VERSION 5.7 ;
  NOWIREEXTENSIONATPIN ON ;
  DIVIDERCHAR "/" ;
  BUSBITCHARS "[]" ;
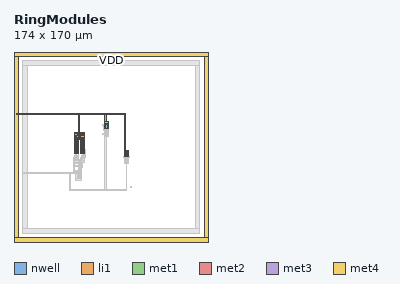
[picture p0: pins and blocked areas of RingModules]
MACRO RingModules
  CLASS BLOCK ;
  FOREIGN RingModules ;
  ORIGIN 12.000 8.000 ;
  SIZE 174.000 BY 170.000 ;
  PIN VDD
    ANTENNADIFFAREA 31.667999 ;
    PORT
      LAYER nwell ;
        RECT 69.250 93.250 72.330 98.220 ;
        RECT 42.340 80.320 45.420 86.020 ;
        RECT 42.330 71.550 45.420 80.320 ;
        RECT 42.330 71.320 45.410 71.550 ;
        RECT 47.890 71.490 50.970 85.960 ;
        RECT 87.170 68.400 90.250 72.370 ;
      LAYER li1 ;
        RECT 69.210 97.520 72.410 99.380 ;
        RECT 69.210 93.810 69.850 97.520 ;
        RECT 71.640 93.810 72.410 97.520 ;
        RECT 69.210 93.640 72.410 93.810 ;
        RECT 69.210 93.550 69.850 93.640 ;
        RECT 71.640 93.580 72.410 93.640 ;
        RECT 69.330 93.530 69.850 93.550 ;
        RECT 69.520 93.520 69.850 93.530 ;
        RECT 42.340 85.550 45.450 90.160 ;
        RECT 42.730 85.460 45.030 85.550 ;
        RECT 47.890 85.480 51.000 90.090 ;
        RECT 42.730 72.110 42.900 85.460 ;
        RECT 43.400 73.015 43.570 84.555 ;
        RECT 44.860 72.110 45.030 85.460 ;
        RECT 42.730 71.940 45.030 72.110 ;
        RECT 48.280 85.400 50.580 85.480 ;
        RECT 48.280 72.050 48.450 85.400 ;
        RECT 48.950 72.955 49.120 84.495 ;
        RECT 50.410 72.050 50.580 85.400 ;
        RECT 48.280 71.880 50.580 72.050 ;
        RECT 86.740 71.800 90.610 73.990 ;
        RECT 86.740 68.960 87.740 71.800 ;
        RECT 87.990 70.905 88.290 71.800 ;
        RECT 87.990 70.400 88.400 70.905 ;
        RECT 88.230 69.865 88.400 70.400 ;
        RECT 89.680 68.960 90.610 71.800 ;
        RECT 86.740 68.800 90.610 68.960 ;
        RECT 87.560 68.790 89.860 68.800 ;
      LAYER met1 ;
        RECT 34.520 107.090 35.520 107.120 ;
        RECT 34.520 106.090 87.870 107.090 ;
        RECT 34.520 106.060 35.520 106.090 ;
        RECT 46.050 89.840 47.050 106.090 ;
        RECT 69.340 99.390 70.340 106.090 ;
        RECT 69.200 98.100 72.360 99.390 ;
        RECT 43.220 89.810 50.550 89.840 ;
        RECT 42.460 89.800 50.550 89.810 ;
        RECT 42.460 88.840 50.810 89.800 ;
        RECT 42.460 87.710 45.220 88.840 ;
        RECT 48.050 88.140 50.810 88.840 ;
        RECT 46.740 87.715 50.810 88.140 ;
        RECT 43.170 84.535 43.480 87.710 ;
        RECT 46.740 85.770 47.165 87.715 ;
        RECT 48.050 87.700 50.810 87.715 ;
        RECT 43.170 83.870 43.600 84.535 ;
        RECT 43.370 73.035 43.600 83.870 ;
        RECT 46.730 84.180 47.170 84.210 ;
        RECT 48.920 84.180 49.150 84.475 ;
        RECT 46.730 83.740 49.150 84.180 ;
        RECT 46.730 83.710 47.170 83.740 ;
        RECT 48.920 72.975 49.150 83.740 ;
        RECT 86.870 73.990 87.870 106.090 ;
        RECT 86.740 73.390 90.610 73.990 ;
        RECT 86.740 71.920 90.650 73.390 ;
        RECT 86.740 71.800 90.610 71.920 ;
        RECT 87.990 70.885 88.290 71.800 ;
        RECT 87.990 70.400 88.430 70.885 ;
        RECT 88.200 69.885 88.430 70.400 ;
      LAYER met2 ;
        RECT 11.560 106.090 35.550 107.090 ;
        RECT 11.560 106.045 12.560 106.090 ;
        RECT 46.740 86.225 47.165 86.250 ;
        RECT 46.710 85.800 47.195 86.225 ;
        RECT 46.740 84.180 47.165 85.800 ;
        RECT 46.700 83.740 47.200 84.180 ;
      LAYER met3 ;
        RECT -10.090 106.065 12.585 107.065 ;
      LAYER met4 ;
        RECT -12.000 158.000 162.000 162.000 ;
        RECT -12.000 -4.000 -8.000 158.000 ;
        RECT 158.000 -4.000 162.000 158.000 ;
        RECT -12.000 -8.000 162.000 -4.000 ;
    END
  END VDD
  OBS
      LAYER pwell ;
        RECT 69.340 87.780 72.140 91.360 ;
        RECT 42.460 65.910 45.260 69.640 ;
        RECT 48.060 65.960 50.860 69.690 ;
        RECT 87.320 64.120 90.100 67.700 ;
        RECT 45.340 49.210 48.140 61.240 ;
      LAYER li1 ;
        RECT 70.540 96.970 71.040 97.140 ;
        RECT 70.310 94.715 70.480 96.755 ;
        RECT 71.100 94.715 71.270 96.755 ;
        RECT 70.540 94.330 71.040 94.500 ;
        RECT 69.260 91.120 69.790 91.220 ;
        RECT 71.670 91.120 72.200 91.180 ;
        RECT 69.260 90.950 72.200 91.120 ;
        RECT 69.260 88.190 69.790 90.950 ;
        RECT 70.490 90.260 70.990 90.430 ;
        RECT 70.260 89.050 70.430 90.090 ;
        RECT 71.050 89.050 71.220 90.090 ;
        RECT 70.490 88.710 70.990 88.880 ;
        RECT 71.670 88.190 72.200 90.950 ;
        RECT 69.260 87.030 72.200 88.190 ;
        RECT 69.270 86.300 72.200 87.030 ;
        RECT 43.630 84.770 44.130 84.940 ;
        RECT 49.180 84.710 49.680 84.880 ;
        RECT 44.190 73.015 44.360 84.555 ;
        RECT 49.740 72.955 49.910 84.495 ;
        RECT 43.630 72.630 44.130 72.800 ;
        RECT 49.180 72.570 49.680 72.740 ;
        RECT 88.460 71.120 88.960 71.290 ;
        RECT 89.020 69.865 89.190 70.905 ;
        RECT 88.460 69.480 88.960 69.650 ;
        RECT 42.700 69.230 45.020 69.400 ;
        RECT 42.700 66.360 42.870 69.230 ;
        RECT 43.610 68.540 44.110 68.710 ;
        RECT 43.380 67.180 43.550 68.370 ;
        RECT 44.170 67.180 44.340 68.370 ;
        RECT 43.610 66.840 44.110 67.010 ;
        RECT 44.850 66.360 45.020 69.230 ;
        RECT 48.300 69.280 50.620 69.450 ;
        RECT 48.300 66.440 48.470 69.280 ;
        RECT 49.210 68.590 49.710 68.760 ;
        RECT 48.980 67.230 49.150 68.420 ;
        RECT 49.770 67.230 49.940 68.420 ;
        RECT 49.210 66.890 49.710 67.060 ;
        RECT 48.030 66.370 49.910 66.440 ;
        RECT 50.450 66.370 50.620 69.280 ;
        RECT 86.720 67.290 90.610 67.460 ;
        RECT 42.440 65.050 45.290 66.360 ;
        RECT 42.430 63.060 45.300 65.050 ;
        RECT 48.030 63.565 50.940 66.370 ;
        RECT 86.720 64.540 87.730 67.290 ;
        RECT 88.460 66.600 88.960 66.770 ;
        RECT 88.230 65.790 88.400 66.430 ;
        RECT 87.990 65.390 88.400 65.790 ;
        RECT 89.020 65.390 89.190 66.430 ;
        RECT 87.990 64.540 88.290 65.390 ;
        RECT 88.460 65.050 88.960 65.220 ;
        RECT 89.670 64.540 90.610 67.290 ;
        RECT 86.720 63.820 90.610 64.540 ;
        RECT 48.060 63.010 50.940 63.565 ;
        RECT 86.710 62.350 90.620 63.820 ;
        RECT 45.580 60.830 47.900 61.000 ;
        RECT 45.580 49.620 45.750 60.830 ;
        RECT 46.490 60.140 46.990 60.310 ;
        RECT 46.260 50.480 46.430 59.970 ;
        RECT 47.050 50.480 47.220 59.970 ;
        RECT 46.490 50.140 46.990 50.310 ;
        RECT 47.730 49.620 47.900 60.830 ;
        RECT 45.580 49.580 47.900 49.620 ;
        RECT 45.330 46.760 48.170 49.580 ;
      LAYER met1 ;
        RECT 67.060 97.225 68.060 97.550 ;
        RECT 67.060 97.170 70.885 97.225 ;
        RECT 67.060 96.940 71.020 97.170 ;
        RECT 67.060 96.875 70.900 96.940 ;
        RECT 67.060 96.550 68.060 96.875 ;
        RECT 70.280 95.785 70.510 96.735 ;
        RECT 67.945 95.430 70.510 95.785 ;
        RECT 67.945 92.370 68.300 95.430 ;
        RECT 70.280 94.735 70.510 95.430 ;
        RECT 70.670 94.530 70.900 96.875 ;
        RECT 71.070 95.775 71.300 96.735 ;
        RECT 71.070 95.525 72.575 95.775 ;
        RECT 71.070 94.735 71.300 95.525 ;
        RECT 70.560 94.300 71.020 94.530 ;
        RECT 70.670 94.270 70.900 94.300 ;
        RECT 68.630 92.370 69.630 92.690 ;
        RECT 72.325 92.680 72.575 95.525 ;
        RECT 67.945 92.340 69.630 92.370 ;
        RECT 67.945 92.040 71.410 92.340 ;
        RECT 67.945 92.015 69.630 92.040 ;
        RECT 68.630 91.690 69.630 92.015 ;
        RECT 68.980 90.810 69.240 91.130 ;
        RECT 69.010 89.555 69.210 90.810 ;
        RECT 70.510 90.230 70.970 90.460 ;
        RECT 70.230 89.610 70.460 90.070 ;
        RECT 70.130 89.555 70.460 89.610 ;
        RECT 69.010 89.355 70.460 89.555 ;
        RECT 67.280 88.875 68.280 89.350 ;
        RECT 70.130 89.300 70.460 89.355 ;
        RECT 70.230 89.070 70.460 89.300 ;
        RECT 70.680 88.910 70.820 90.230 ;
        RECT 71.110 90.070 71.410 92.040 ;
        RECT 71.950 91.680 72.950 92.680 ;
        RECT 72.355 91.255 72.550 91.680 ;
        RECT 72.325 90.935 72.585 91.255 ;
        RECT 71.020 89.430 71.410 90.070 ;
        RECT 71.020 89.070 71.250 89.430 ;
        RECT 70.510 88.875 70.970 88.910 ;
        RECT 67.280 88.645 70.975 88.875 ;
        RECT 67.280 88.350 68.280 88.645 ;
        RECT 69.430 87.410 70.430 87.470 ;
        RECT 69.230 86.290 72.200 87.410 ;
        RECT 43.650 84.910 44.110 84.970 ;
        RECT 43.650 84.740 49.660 84.910 ;
        RECT 43.770 72.855 43.970 84.740 ;
        RECT 49.200 84.680 49.660 84.740 ;
        RECT 44.160 74.320 44.390 84.535 ;
        RECT 44.160 73.970 45.880 74.320 ;
        RECT 44.160 73.035 44.390 73.970 ;
        RECT 45.530 72.855 45.880 73.970 ;
        RECT 43.725 72.830 45.880 72.855 ;
        RECT 43.650 72.600 45.880 72.830 ;
        RECT 49.340 72.770 49.570 84.680 ;
        RECT 49.710 74.330 49.940 84.475 ;
        RECT 49.710 74.320 51.750 74.330 ;
        RECT 49.710 73.970 51.770 74.320 ;
        RECT 49.710 72.975 49.940 73.970 ;
        RECT 43.725 72.505 45.880 72.600 ;
        RECT 49.200 72.540 49.660 72.770 ;
        RECT 43.350 70.120 44.350 71.120 ;
        RECT 43.780 68.740 43.940 70.120 ;
        RECT 43.630 68.510 44.090 68.740 ;
        RECT 43.350 68.020 43.580 68.350 ;
        RECT 41.480 67.640 43.580 68.020 ;
        RECT 41.480 62.270 41.860 67.640 ;
        RECT 43.350 67.200 43.580 67.640 ;
        RECT 43.780 67.040 43.940 68.510 ;
        RECT 44.140 68.020 44.370 68.350 ;
        RECT 45.530 68.020 45.880 72.505 ;
        RECT 48.980 70.190 49.980 71.190 ;
        RECT 51.370 71.120 51.770 73.970 ;
        RECT 49.370 68.790 49.575 70.190 ;
        RECT 51.130 70.120 52.130 71.120 ;
        RECT 49.230 68.560 49.690 68.790 ;
        RECT 51.370 68.770 51.770 70.120 ;
        RECT 48.950 68.020 49.180 68.400 ;
        RECT 44.140 67.675 45.880 68.020 ;
        RECT 44.140 67.670 45.840 67.675 ;
        RECT 44.140 67.200 44.370 67.670 ;
        RECT 47.440 67.590 49.180 68.020 ;
        RECT 43.630 66.810 44.090 67.040 ;
        RECT 45.940 65.780 46.480 65.810 ;
        RECT 42.860 65.240 46.480 65.780 ;
        RECT 42.860 64.760 43.450 65.240 ;
        RECT 45.940 65.210 46.480 65.240 ;
        RECT 42.410 63.320 45.270 64.760 ;
        RECT 47.455 62.305 47.860 67.590 ;
        RECT 48.950 67.250 49.180 67.590 ;
        RECT 49.370 67.090 49.575 68.560 ;
        RECT 49.740 68.010 49.970 68.400 ;
        RECT 51.370 68.010 51.790 68.770 ;
        RECT 49.740 67.650 51.790 68.010 ;
        RECT 49.740 67.250 49.970 67.650 ;
        RECT 49.230 66.860 49.690 67.090 ;
        RECT 48.660 65.150 49.280 65.710 ;
        RECT 48.690 64.740 49.250 65.150 ;
        RECT 48.040 63.300 50.910 64.740 ;
        RECT 46.615 62.270 49.510 62.305 ;
        RECT 41.480 61.910 49.510 62.270 ;
        RECT 41.480 61.890 47.040 61.910 ;
        RECT 47.455 61.900 49.510 61.910 ;
        RECT 43.380 60.495 44.380 60.820 ;
        RECT 43.380 60.145 47.035 60.495 ;
        RECT 43.380 59.820 44.380 60.145 ;
        RECT 46.510 60.110 46.970 60.145 ;
        RECT 43.440 53.900 44.440 56.080 ;
        RECT 32.120 52.900 44.440 53.900 ;
        RECT 37.835 39.125 38.525 52.900 ;
        RECT 43.440 48.460 44.440 52.900 ;
        RECT 46.230 51.030 46.460 59.950 ;
        RECT 46.010 50.500 46.460 51.030 ;
        RECT 46.010 48.700 46.320 50.500 ;
        RECT 46.650 50.340 46.820 60.110 ;
        RECT 47.020 58.940 47.250 59.950 ;
        RECT 49.105 58.945 49.510 61.900 ;
        RECT 48.270 58.940 49.510 58.945 ;
        RECT 47.020 58.540 49.510 58.940 ;
        RECT 47.020 58.510 48.750 58.540 ;
        RECT 47.020 50.500 47.250 58.510 ;
        RECT 46.510 50.110 46.970 50.340 ;
        RECT 45.460 48.460 47.970 48.700 ;
        RECT 43.440 47.460 47.970 48.460 ;
        RECT 45.460 47.160 47.970 47.460 ;
        RECT 69.420 39.125 70.540 86.290 ;
        RECT 88.615 71.320 88.765 71.355 ;
        RECT 88.480 71.090 88.940 71.320 ;
        RECT 88.615 69.680 88.840 71.090 ;
        RECT 88.990 70.620 89.220 70.885 ;
        RECT 88.990 69.885 89.280 70.620 ;
        RECT 88.480 69.450 88.940 69.680 ;
        RECT 85.750 68.220 87.050 68.690 ;
        RECT 88.615 68.220 88.840 69.450 ;
        RECT 85.750 67.980 88.840 68.220 ;
        RECT 85.750 67.520 87.050 67.980 ;
        RECT 88.615 66.800 88.840 67.980 ;
        RECT 89.100 68.220 89.280 69.885 ;
        RECT 90.480 68.220 91.780 68.750 ;
        RECT 89.100 67.980 91.780 68.220 ;
        RECT 88.480 66.570 88.940 66.800 ;
        RECT 88.200 65.790 88.430 66.410 ;
        RECT 87.990 65.410 88.430 65.790 ;
        RECT 87.990 64.540 88.290 65.410 ;
        RECT 88.615 65.250 88.840 66.570 ;
        RECT 89.100 66.410 89.280 67.980 ;
        RECT 90.480 67.580 91.780 67.980 ;
        RECT 88.990 65.540 89.280 66.410 ;
        RECT 88.990 65.410 89.220 65.540 ;
        RECT 88.480 65.020 88.940 65.250 ;
        RECT 88.615 65.000 88.840 65.020 ;
        RECT 88.615 64.995 88.765 65.000 ;
        RECT 86.720 64.460 90.610 64.540 ;
        RECT 86.700 62.990 90.610 64.460 ;
        RECT 86.720 62.350 90.610 62.990 ;
        RECT 88.375 39.125 89.065 62.350 ;
        RECT 92.290 40.915 93.290 41.990 ;
        RECT 37.835 38.435 89.065 39.125 ;
      LAYER met2 ;
        RECT 68.950 91.070 69.270 91.100 ;
        RECT 72.295 91.070 72.615 91.225 ;
        RECT 68.950 90.965 72.615 91.070 ;
        RECT 68.950 90.870 72.540 90.965 ;
        RECT 68.950 90.840 69.270 90.870 ;
        RECT 45.910 65.710 46.510 65.780 ;
        RECT 48.690 65.710 49.250 65.740 ;
        RECT 45.830 65.150 49.250 65.710 ;
        RECT 45.940 62.340 46.480 65.150 ;
        RECT 48.690 65.120 49.250 65.150 ;
        RECT 41.180 61.800 46.480 62.340 ;
        RECT 41.195 55.740 41.710 61.800 ;
        RECT 43.410 55.740 44.470 56.050 ;
        RECT 41.195 55.225 44.470 55.740 ;
        RECT 43.410 55.050 44.470 55.225 ;
        RECT 32.150 53.900 33.150 53.930 ;
        RECT 21.580 52.900 33.150 53.900 ;
        RECT 21.580 52.855 22.580 52.900 ;
        RECT 32.150 52.870 33.150 52.900 ;
      LAYER met3 ;
        RECT 10.110 52.875 22.605 53.875 ;
      LAYER met4 ;
        RECT -4.000 150.000 154.000 154.000 ;
        RECT -4.000 53.875 0.000 150.000 ;
        RECT 10.135 53.875 11.135 53.880 ;
        RECT -4.000 52.875 11.135 53.875 ;
        RECT -4.000 4.000 0.000 52.875 ;
        RECT 10.135 52.870 11.135 52.875 ;
        RECT 150.000 4.000 154.000 150.000 ;
        RECT -4.000 0.000 154.000 4.000 ;
  END
END RingModules
END LIBRARY

